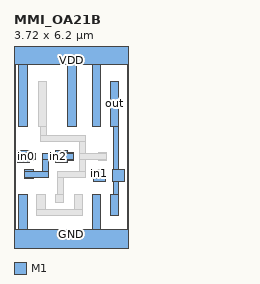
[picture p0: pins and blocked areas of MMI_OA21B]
MACRO MMI_OA21B
	CLASS CORE ;
	FOREIGN MMI_OA21B 0 0 ;
	SIZE 3.72 BY 6.2 ;
	SYMMETRY X Y ;
	SITE CORE1 ;
	PIN out
		DIRECTION output ;
		USE SIGNAL ;
		PORT
			LAYER M1 ;
			RECT 3.145 3.78 3.425 5.25 ;
			LAYER M1 ;
			RECT 3.235 2.36 3.425 3.78 ;
			LAYER M1 ;
			RECT 3.22 1.98 3.6 2.36 ;
			LAYER M1 ;
			RECT 3.235 1.555 3.425 1.98 ;
			LAYER M1 ;
			RECT 3.145 0.855 3.425 1.555 ;
		END
		AntennaDiffArea 0.91245 ;
	END out
	PIN in1
		DIRECTION input ;
		USE SIGNAL ;
		PORT
			LAYER M1 ;
			RECT 2.545 2.08 2.98 2.36 ;
			LAYER M1 ;
			RECT 2.6 1.98 2.98 2.08 ;
		END
		AntennaGateArea 0.3465 ;
	END in1
	PIN GND
		DIRECTION inout ;
		USE GROUND ;
		PORT
			LAYER M1 ;
			RECT 0.16 0.42 0.44 1.555 ;
			LAYER M1 ;
			RECT 2.555 0.42 2.835 1.555 ;
			LAYER M1 ;
			RECT 0 -0.42 3.72 0.42 ;
		END
	END GND
	PIN in2
		DIRECTION input ;
		USE SIGNAL ;
		PORT
			LAYER M1 ;
			RECT 1.36 2.93 1.74 2.98 ;
			LAYER M1 ;
			RECT 1.36 2.885 1.945 2.93 ;
			LAYER M1 ;
			RECT 0.93 2.695 1.945 2.885 ;
			LAYER M1 ;
			RECT 0.355 2.31 0.635 2.35 ;
			LAYER M1 ;
			RECT 0.93 2.31 1.125 2.695 ;
			LAYER M1 ;
			RECT 1.36 2.65 1.945 2.695 ;
			LAYER M1 ;
			RECT 1.36 2.6 1.74 2.65 ;
			LAYER M1 ;
			RECT 0.355 2.115 1.125 2.31 ;
			LAYER M1 ;
			RECT 0.355 2.07 0.635 2.115 ;
		END
		AntennaGateArea 0.3465 ;
	END in2
	PIN VDD
		DIRECTION inout ;
		USE POWER ;
		PORT
			LAYER M1 ;
			RECT 0 5.78 3.72 6.62 ;
			LAYER M1 ;
			RECT 0.16 3.78 0.44 5.78 ;
			LAYER M1 ;
			RECT 1.755 3.78 2.035 5.78 ;
			LAYER M1 ;
			RECT 2.555 3.78 2.835 5.78 ;
		END
	END VDD
	PIN in0
		DIRECTION input ;
		USE SIGNAL ;
		PORT
			LAYER M1 ;
			RECT 0.12 2.93 0.5 2.98 ;
			LAYER M1 ;
			RECT 0.12 2.885 0.635 2.93 ;
			LAYER M1 ;
			RECT 0.12 2.695 0.69 2.885 ;
			LAYER M1 ;
			RECT 0.12 2.65 0.635 2.695 ;
			LAYER M1 ;
			RECT 0.12 2.6 0.5 2.65 ;
		END
		AntennaGateArea 0.231 ;
	END in0
	OBS
		LAYER M1 ;
		RECT 0.795 3.78 1.075 5.25 ;
		LAYER M1 ;
		RECT 0.88 3.465 1.075 3.78 ;
		LAYER M1 ;
		RECT 0.88 3.27 2.345 3.465 ;
		LAYER M1 ;
		RECT 2.15 2.885 2.345 3.27 ;
		LAYER M1 ;
		RECT 2.75 2.885 3.03 2.93 ;
		LAYER M1 ;
		RECT 2.15 2.695 3.03 2.885 ;
		LAYER M1 ;
		RECT 2.15 2.31 2.345 2.695 ;
		LAYER M1 ;
		RECT 2.75 2.65 3.03 2.695 ;
		LAYER M1 ;
		RECT 1.43 2.115 2.345 2.31 ;
		LAYER M1 ;
		RECT 1.43 1.555 1.62 2.115 ;
		LAYER M1 ;
		RECT 0.75 1.05 1.03 1.555 ;
		LAYER M1 ;
		RECT 1.34 1.275 1.62 1.555 ;
		LAYER M1 ;
		RECT 1.965 1.05 2.245 1.555 ;
		LAYER M1 ;
		RECT 0.75 0.855 2.245 1.05 ;
	END
END MMI_OA21B
